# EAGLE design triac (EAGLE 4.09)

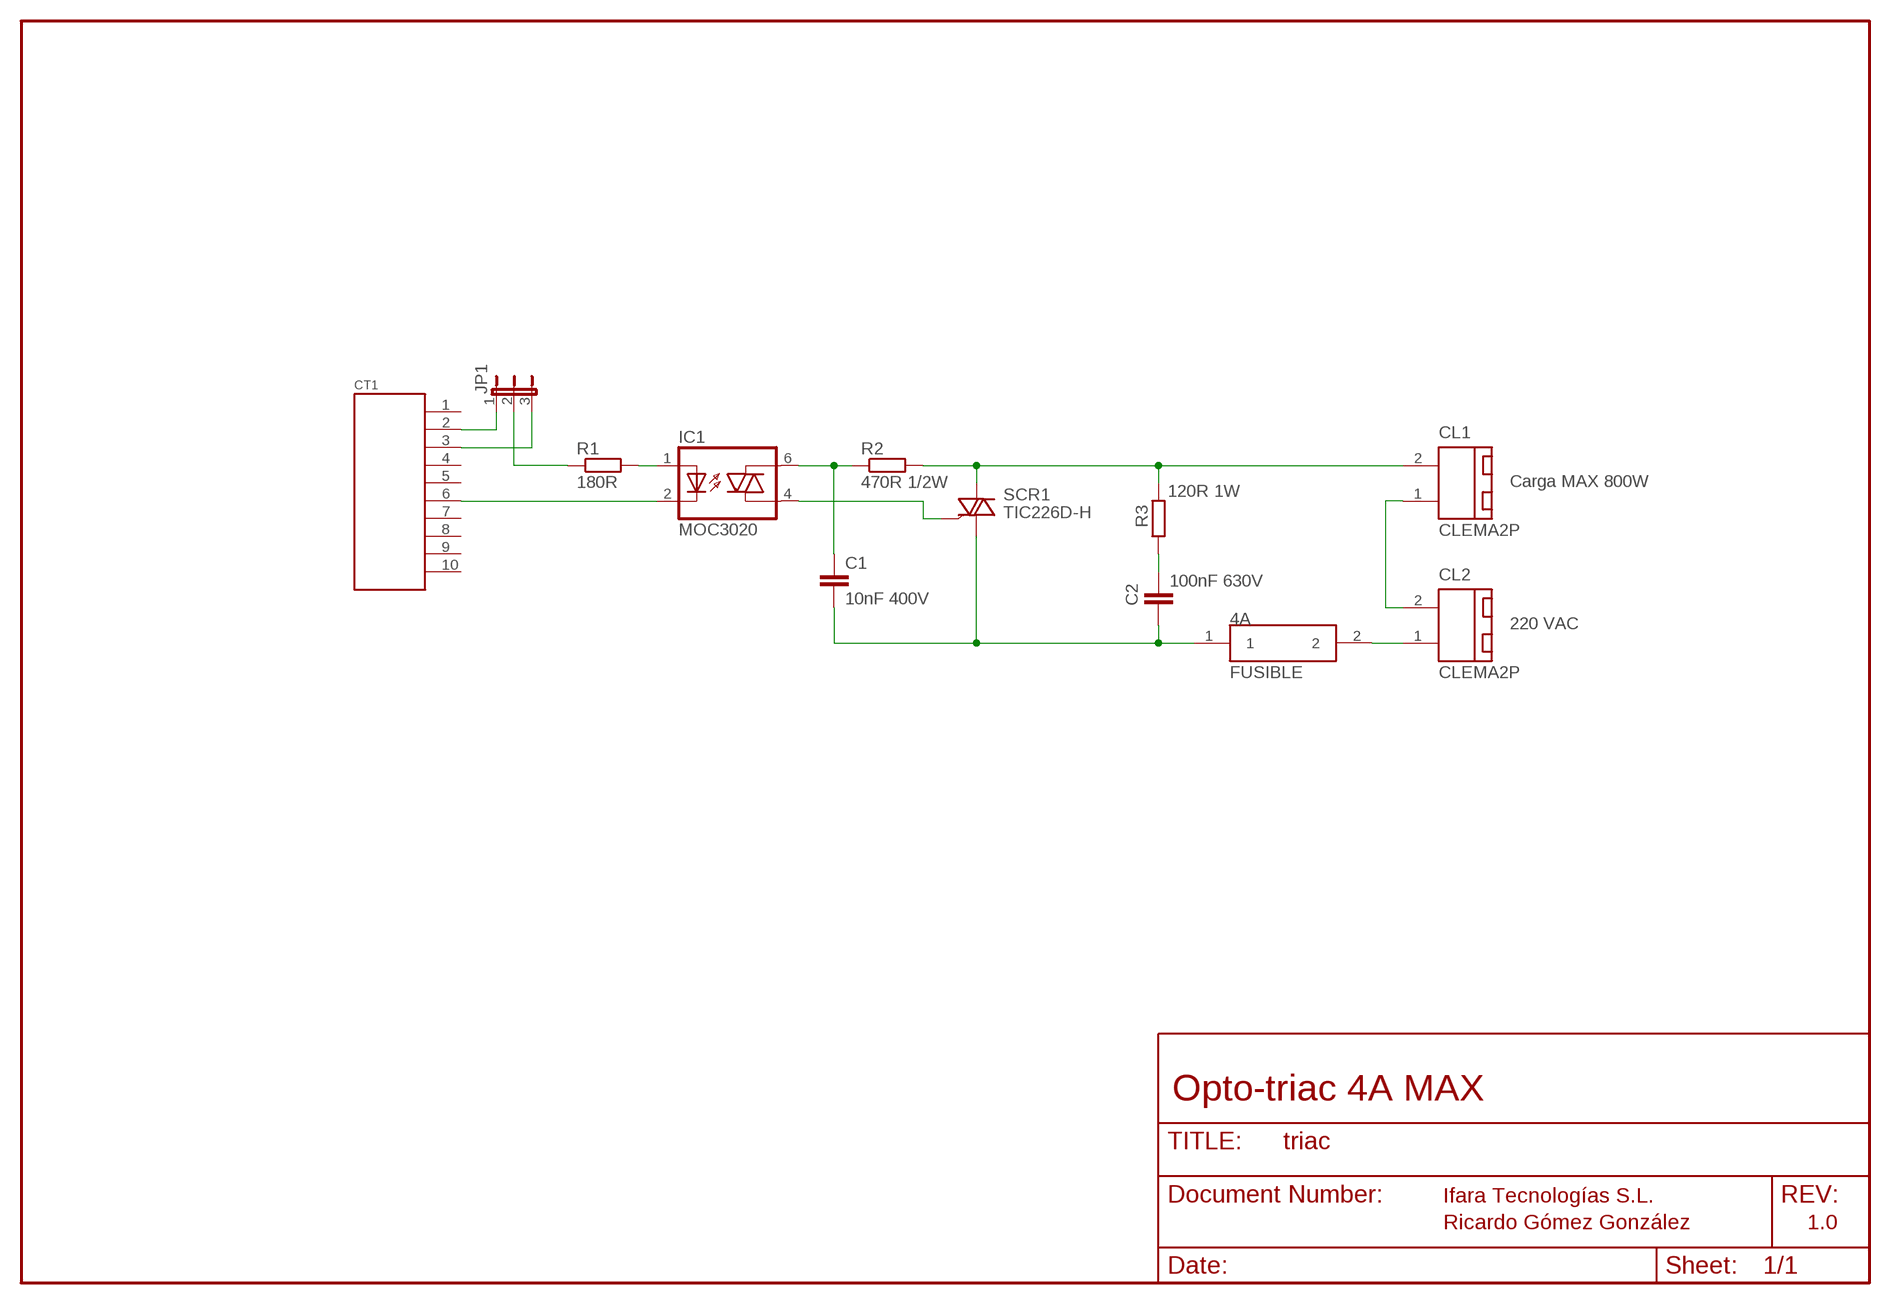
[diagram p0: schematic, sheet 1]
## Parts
4A  FUSIBLE  [FUSIBLE]
C1  10nF 400V  C-EU102-043X133  [C102-043X133]
C2  100nF 630V  C-EU225-062X268  [C225-062X268]
CL1  CLEMA2P  [C2P]
CL2  CLEMA2P  [C2P]
CT1  CTCONA  [CTCON]
IC1  MOC3020  [DIL06]
JP1  JUMPER3R  [JP3R]
R1  180R  RESISTENCIA10  [R207/10]
R2  470R 1/2W  RESISTENCIA10  [R207/10]
R3  120R 1W  R-EU_0411/12  [0411/12]
SCR1  TIC226D-H  TRIACS/TIC226D-H  [TO220DL]

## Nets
N$1: C1.1 IC1.6(A2) R2.1
N$2: CL1.2 R2.2 R3.2 SCR1.A2
N$3: IC1.4(A1) SCR1.G
N$4: 4A.1 C1.2 C2.2 SCR1.A1
N$5: JP1.2 R1.1
N$6: CL1.1 CL2.2
N$7: IC1.1(A) R1.2
N$8: CT1.2 JP1.1
N$9: CT1.6 IC1.2(C)
N$10: 4A.2 CL2.1
N$11: CT1.3 JP1.3
N$13: C2.1 R3.1
Unconnected: CT1.1 CT1.4 CT1.5 CT1.7 CT1.8 CT1.9 CT1.10

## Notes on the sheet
- Carga MAX 800W
- 220 VAC
- Opto-triac 4A MAX
- Ifara Tecnologías S.L.
- Ricardo Gómez González | 1.0

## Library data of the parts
4A = custom-2004-ricardo:FUSIBLE
C1 C2 = rcl:C-EU: CAPACITOR, European symbol
CL1 CL2 = ifara2005:CLEMA2P: Clema doble pequeña para circuito impreso
CT1 = andres-2002:CTCON: Conector compatible CT
IC1 = ifara2005:MOC3020
JP1 = ifara2005:JUMPER3
R1 R2 = ifara2005:RESISTENCIA: Resistencia de paso 10mm
R3 = rcl:R-EU_: RESISTOR, European symbol
SCR1 = ifara2005:TRIACS

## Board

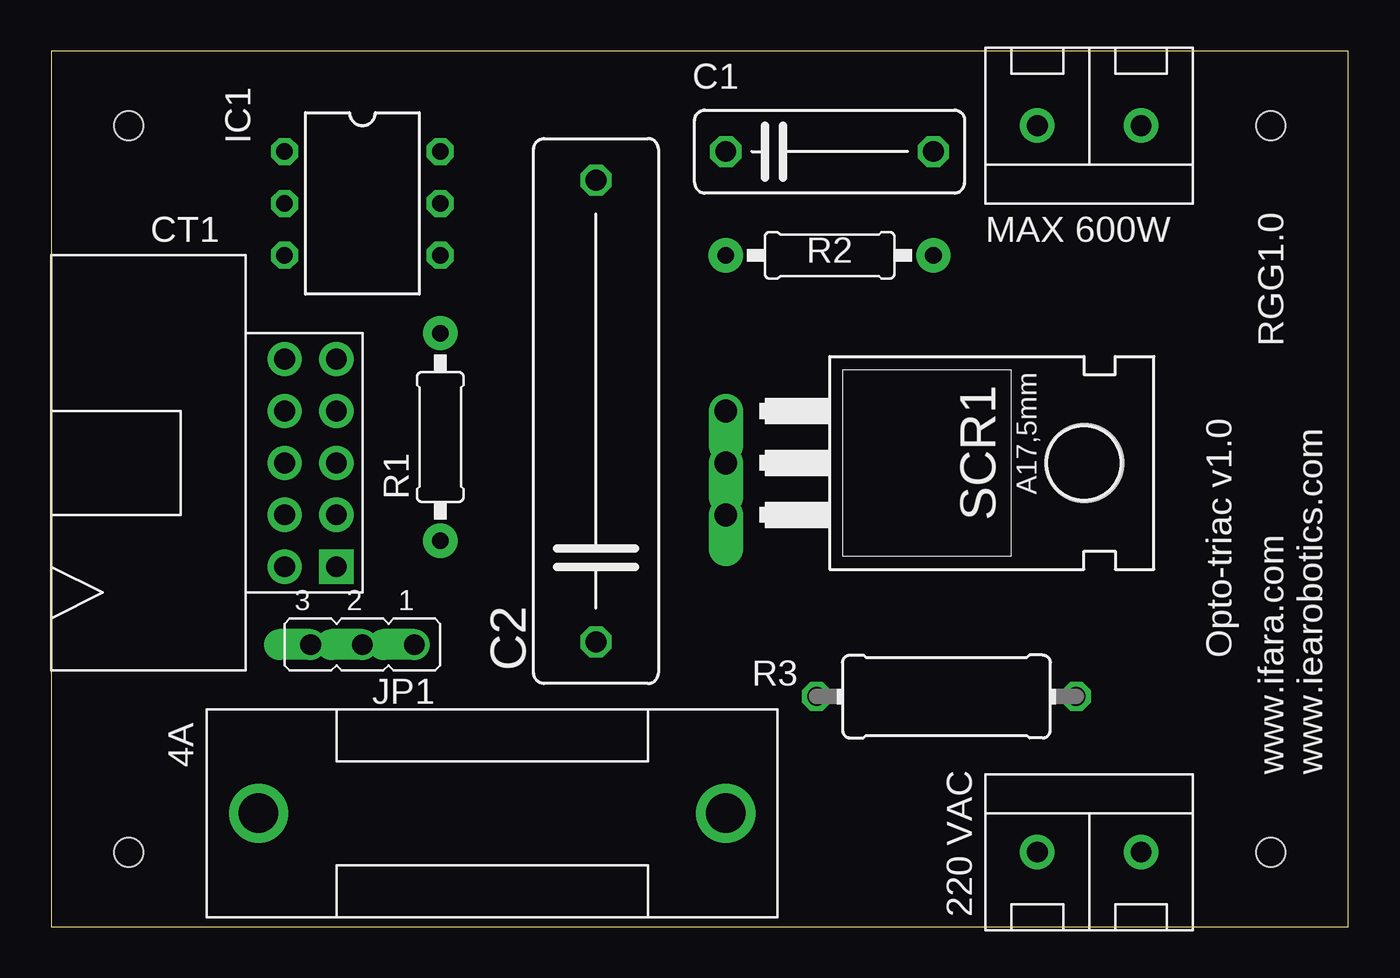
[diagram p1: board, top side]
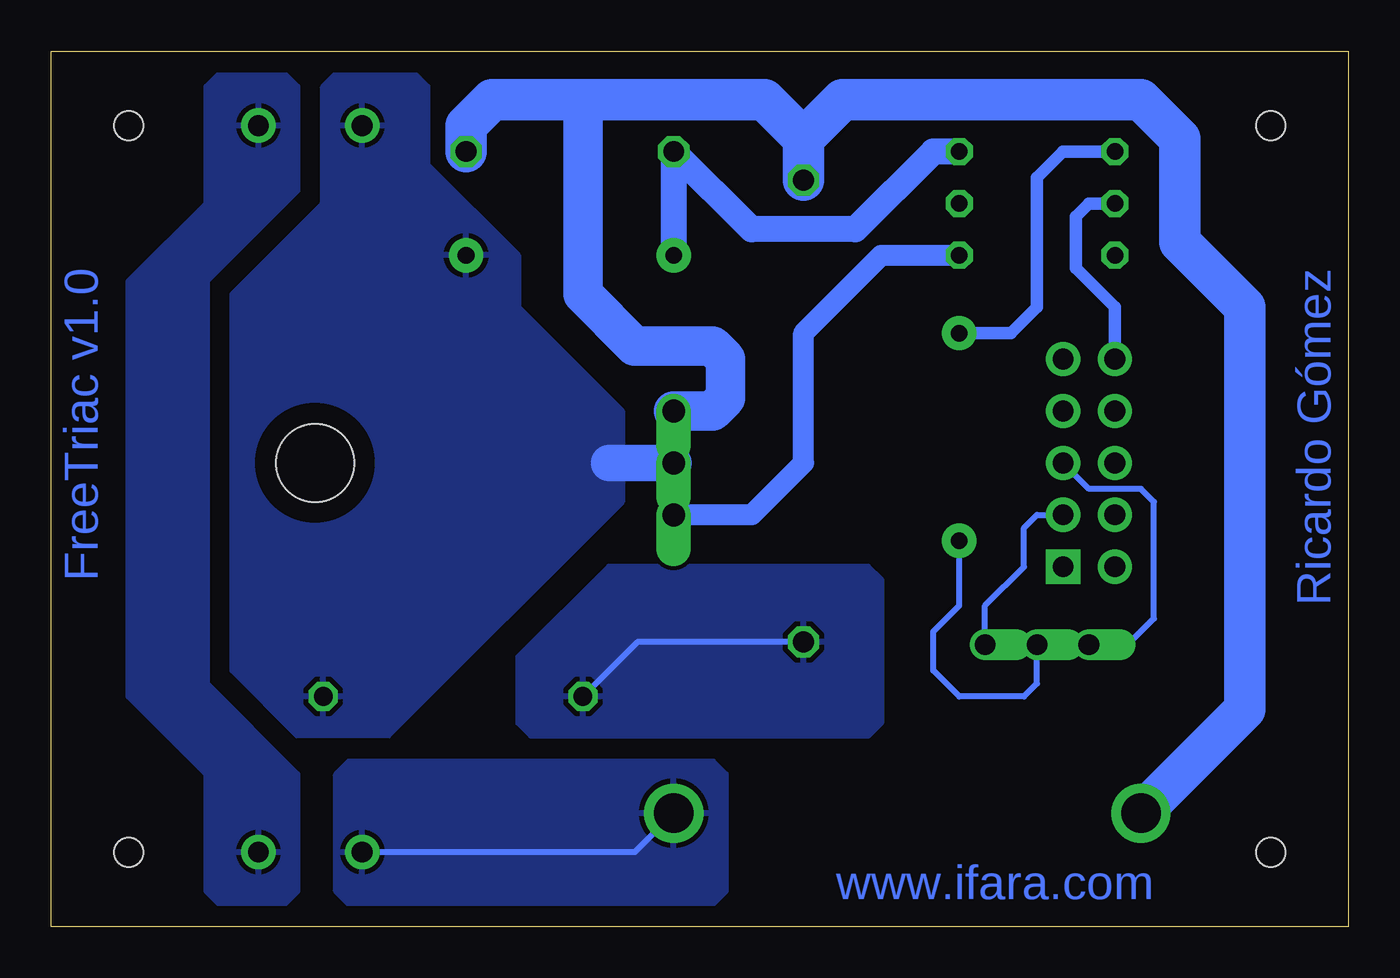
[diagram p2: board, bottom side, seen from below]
Size 63.48 x 42.85 mm. Coordinates in mm from the lower left corner, seen from the top.
Outline: 0,0 63.48,0 63.48,42.85 0,42.85 0,0
Copper layers used: Bottom
Holes 1.42 mm at 59.68,3.65 59.68,39.2 3.81,39.2 3.81,3.65
Holes 3.81 mm at 50.56,22.69

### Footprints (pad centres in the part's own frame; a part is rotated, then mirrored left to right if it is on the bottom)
FUSIBLE = drill 1.93 round: 1 0,0; 2 22.86,0
C102-043X133 = drill 1.016 octagon: 1 -5.08,0; 2 5.08,0
C225-062X268 = drill 1.016 octagon: 1 -11.303,0; 2 11.303,0
C2P = drill 1.016 pad 1.676 round: 1 -2.54,0; 2 2.54,0
CTCON = drill 1.016 pad 1.676 square: 1 0,0 | drill 1.016 pad 1.676 round: 2 2.54,0; 3 5.08,0; 4 7.62,0; 5 10.16,0; 6 10.16,2.54; 7 7.62,2.54; 8 5.08,2.54; 9 2.54,2.54; 10 0,2.54
DIL06 = drill 0.813 octagon: 1 -2.54,-2.54; 2 0,-2.54; 3 2.54,-2.54; 4 2.54,5.08; 5 0,5.08; 6 -2.54,5.08
JP3R = drill 1.016 offset: 1 1.27,1.27; 2 3.81,1.27; 3 6.35,1.27
R207/10 = drill 0.813 pad 1.676 round: 1 -5.08,0; 2 5.08,0
0411/12 = drill 0.914 octagon: 1 -6.35,0; 2 6.35,0
TO220DL = drill 1.118 offset: A1 -2.54,-7.62; A2 0,-7.62; G 2.54,-7.62

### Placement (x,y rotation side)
4A  10.15,5.55 0 top
C1  38.09,37.94 0 top
C2  26.67,25.23 90 top
CL1  50.79,39.2 180 top
CL2  50.79,3.65 0 top
CT1  13.96,17.62 90 top
IC1  13.96,35.4 270 top
JP1  19.05,15.08 180 top
R1  19.05,23.96 90 top
R2  38.09,32.86 0 top
R3  43.81,11.27 0 top
SCR1  40.63,22.7 270 top

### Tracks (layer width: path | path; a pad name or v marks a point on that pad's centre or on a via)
N$1
  Bottom 1.27: R2.1 C1.1 29.21,34.12 24.12,34.12 20.32,37.94 IC1.6
N$2
  Bottom 1.778: SCR1.A2 36.19,22.7
  pour Bottom: 35.55,25.23 35.55,20.79 46.98,9.36 51.43,9.36 54.6,12.54 54.6,30.95 50.16,35.4 50.16,41.11 49.52,41.74 45.71,41.74 45.08,41.11 45.08,37.3 40.63,32.86 40.63,30.32
N$3
  Bottom 1.016: IC1.4 22.86,32.86 26.67,29.05 26.67,22.7 29.21,20.16 SCR1.G
N$4
  Bottom 1.93: SCR1.A1 31.11,25.23 30.48,25.87 30.48,27.78 31.11,28.41 34.92,28.41 37.46,30.95 37.46,40.48
  Bottom 2.032: 26.67,38.57 24.76,40.48 10.15,40.48 8.25,38.57 8.25,33.49 5.08,30.32 5.08,10.63 4A.1 | 26.67,38.57 C2.2 | 26.67,38.57 28.57,40.48 37.46,40.48 41.9,40.48 43.17,39.2 C1.2
N$5
  Bottom 0.305: R1.1 19.05,15.71 20.32,14.44 20.32,12.54 19.05,11.27 15.87,11.27 15.23,11.9 JP1.2
N$6
  pour Bottom: 51.43,7.46 51.43,1.74 52.06,1.1 55.24,1.1 55.88,1.74 55.88,7.46 59.68,11.27 59.68,31.59 55.88,35.4 55.88,41.11 55.24,41.74 52.06,41.74 51.43,41.11 51.43,36.03 55.88,31.59 55.88,11.9
N$7
  Bottom 0.61: IC1.1 13.96,37.94 15.23,36.66 15.23,30.32 16.51,29.05 R1.2
N$8
  Bottom 0.305: CT1.2 15.23,20.16 15.87,19.52 15.87,17.62 17.78,15.71 JP1.1
N$9
  Bottom 0.61: IC1.2 12.69,35.4 13.33,34.76 13.33,32.22 11.42,30.32 CT1.6
N$10
  Bottom 0.305: 4A.2 34.92,3.65 CL2.1
  pour Bottom: 30.48,7.46 30.48,1.74 31.11,1.1 48.89,1.1 49.52,1.74 49.52,7.46 48.89,8.09 31.11,8.09
N$11
  Bottom 0.305: JP1.3 10.79,13.81 9.52,15.08 9.52,20.79 10.15,21.43 12.69,21.43 CT1.3
N$13
  Bottom 0.305: C2.1 34.79,13.93 R3.1
  pour Bottom: 22.86,16.98 23.49,17.62 36.19,17.62 40.63,13.17 40.63,10 40,9.36 23.49,9.36 22.86,10

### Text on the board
Bottom: Ricardo Gómez | FreeTriac v1.0 | www.ifara.com
tNames: MAX 600W | RGG1.0 | Opto-triac v1.0 | www.ifara.com | www.iearobotics.com | 220 VAC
